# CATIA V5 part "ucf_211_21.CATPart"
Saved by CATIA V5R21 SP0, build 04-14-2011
Part number: ucf_211_21
Bounding box of the stored display mesh (mm): x -35 to 35, y -33.4 to 22.2, z -34.808 to 34.808
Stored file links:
  C:\TPO v2\SharedFS\Outgoing\ucf_211_21.CATPart

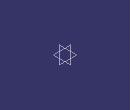
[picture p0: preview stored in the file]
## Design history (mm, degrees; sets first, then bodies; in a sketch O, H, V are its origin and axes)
AxisSystem1: origin (0, 0, 0), X (1, 0, 0), Y (0, 1, 0), Z (0, 0, 1)
Body1 "ucf_211_21" (main body)
  Solid1: solid without history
